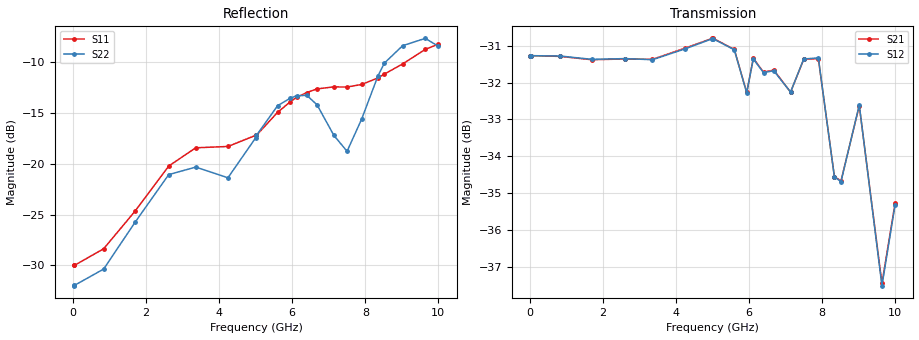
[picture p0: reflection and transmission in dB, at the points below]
! Integrated Device Technology
! Corporate Headquarters
! 6024 Silver Creek Valley Road
! San Jose, CA 95138  USA
! Phone:  1-408-284-8200
! Toll Free:  1-800-223-1366
! Webpage:  http://www.idt.com/
! Timing and RF Division
! 515 Groton Road, Suite 102
! Westford, MA 01886-6024
! Device:  F1958
! Description: 7-bit 0.25 dB Digital Step Attenuator
! Frequency:  0.001 -  6.000 GHz
! Package:  4x4 mm Thin QFN Plastic Package: 24 pin
! Ports:  2 RF, 12 DC
!  Pin  1  = D0
!  Pin  2  = VDD
!  Pin  3  = VMODE
!  Pin  4  = GND
!  Pin  5  = RF1  =  Port 1
!  Pin  6  = GND
!  Pin  7  = GND
!  Pin  8  = GND
!  Pin  9  = GND
!  Pin 10  = GND
!  Pin 11  = GND
!  Pin 12  = GND
!  Pin 13  = GND
!  Pin 14  = RF2  =  Port 2
!  Pin 15  = GND
!  Pin 16  = LE
!  Pin 17  = CLK
!  Pin 18  = DATA
!  Pin 19  = D6
!  Pin 20  = D5
!  Pin 21  = D4
!  Pin 22  = D3
!  Pin 23  = D2
!  Pin 24  = D1
! State:  122
! Atten State:  30.50 dB
! Voltage:  +3.30 Volts
! Current:  0.258 mA
! Data:  The device was measured on a F1958 evaluation board which has
!  individual transmission lines to the RF pins.  Data was collected
!  using a calibrated network analyzer.  The evaluation board was
!  de-embedded using Automatic Fixture Removal (AFR).
!  The reference plane is the edge of the package pin.
! Misc:
!  Action Tracker AT0419
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# GHz S dB R 50
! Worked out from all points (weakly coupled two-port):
!   500 points, 20 MHz to 10 GHz, reference 50 ohm
!   highest |S21| = -30.80 dB at 5 GHz (marker M1); lowest = -37.5 dB at 9.64 GHz (marker M2)
!   lowest |S11| = -30.0 dB at 40 MHz (marker M3), VSWR 1.07, Z = 46.9 - j0.045 ohm
!   |S11| at or under -10 dB: start of sweep to 9.056 GHz
!   |S22| runs from -32.2 to -7.4 dB; largest |S21 - S12| = 0.00034
!   S11 on the Smith chart (normalised r, x): 20 MHz: 0.94, -0.00; 6.4 GHz: 0.67, +0.17; 10 GHz: 0.67, +0.60
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0.02  -29.96 -178.9  -31.29 -0.2  -31.27 -0.1  -31.98 -178.9
0.04  -29.99 -179.1  -31.27 -0.3  -31.27 -0.3  -31.95 -178.4
0.84  -28.36 171.7  -31.29 -8.9  -31.28 -8.9  -30.35 172.9
1.7  -24.67 171.8  -31.38 -17.7  -31.37 -17.7  -25.76 171.9
2.62  -20.25 177.5  -31.36 -27.3  -31.35 -27.3  -21.09 -179.2
3.36  -18.46 -175.5  -31.37 -35.6  -31.38 -35.8  -20.35 -169.3
4.24  -18.33 -179.0  -31.07 -45.0  -31.09 -45.1  -21.40 169.2
5  -17.24 161.7  -30.80 -54.6  -30.81 -54.6  -17.48 137.6
5.02  -17.24 160.9  -30.80 -54.9  -30.81 -55.0  -17.25 138.6
5.6  -14.98 150.9  -31.10 -63.7  -31.11 -63.6  -14.33 140.3
5.94  -13.97 148.4  -32.27 -67.1  -32.28 -67.0  -13.61 148.6
6.12  -13.51 148.7  -31.34 -67.6  -31.36 -67.6  -13.35 151.5
6.4  -13.04 147.8  -31.72 -72.3  -31.73 -72.4  -13.32 155.5
6.68  -12.68 146.6  -31.66 -74.9  -31.68 -74.8  -14.25 157.4
7.14  -12.49 142.6  -32.26 -80.0  -32.26 -79.8  -17.25 151.4
7.5  -12.50 138.0  -31.37 -83.6  -31.36 -83.4  -18.80 119.8
7.9  -12.25 128.7  -31.35 -99.6  -31.33 -99.6  -15.64 89.6
8.34  -11.62 118.7  -34.56 -105.1  -34.57 -105.1  -11.46 84.2
8.52  -11.23 115.3  -34.67 -96.6  -34.69 -96.6  -10.16 87.6
9.02  -10.24 107.5  -32.63 -106.0  -32.61 -105.7  -8.45 97.9
9.64  -8.81 101.0  -37.46 -100.0  -37.52 -100.0  -7.73 110.6
10  -8.29 99.4  -35.28 -85.2  -35.32 -85.0  -8.51 113.8
